PROGRAM p03_SR1
VAR
	// Set
	S0: BOOL;
	// Reset
	S1: BOOL;
	// Q
	L0: BOOL;
END_VAR

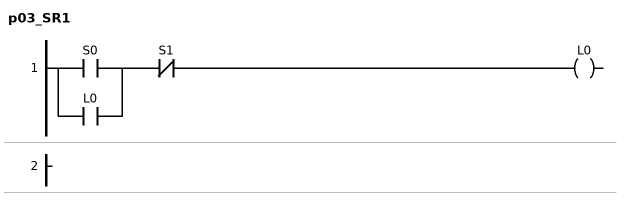
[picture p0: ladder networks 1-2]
// NETWORK 1
L0 := (S0 OR L0) AND NOT S1;

// NETWORK 2

END_PROGRAM
